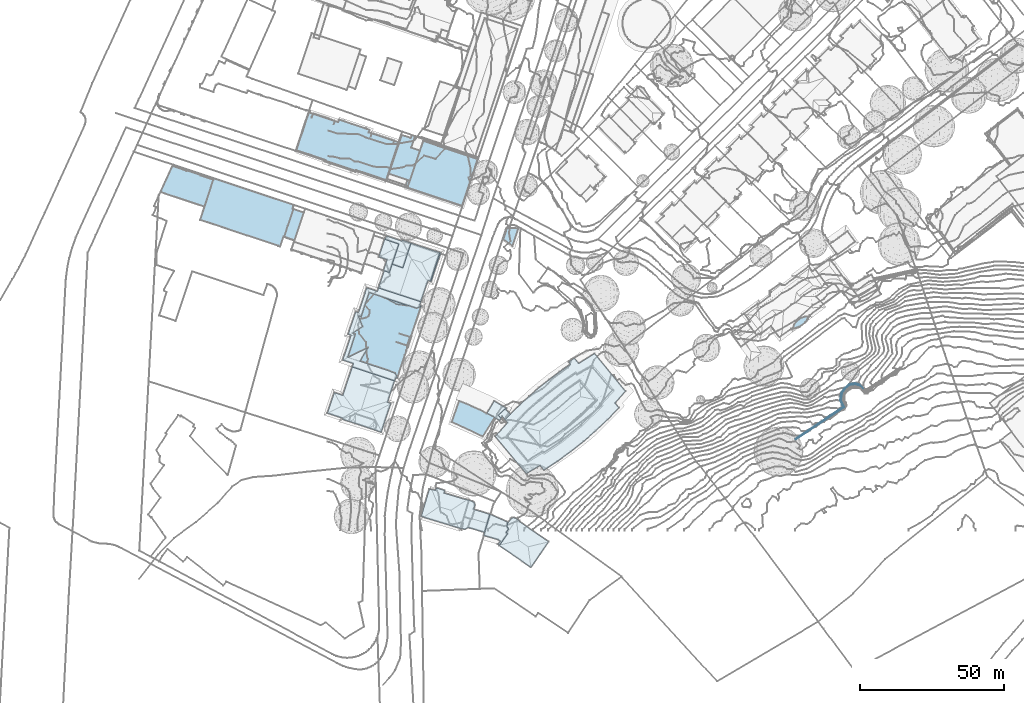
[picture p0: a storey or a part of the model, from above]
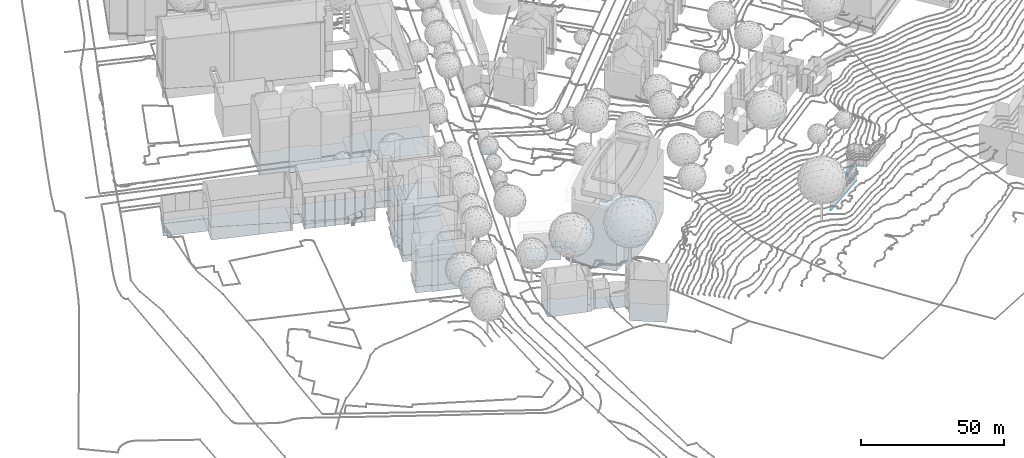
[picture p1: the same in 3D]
Properties of the parts of a building model (IFC4)

# File
Description: ViewDefinition [CoordinationView]
Time: 2024-08-21T15:45:22
Written by: TpxIfclib v0.1
Made in: TpxIfclib v0.1

# IfcGeographicElement (454)
Name | In
TPX_GROUND | TPX_GROUND | PredefinedType: TERRAIN
Cadastre 0 | TPX_CADASTRES
Cadastre 1 | TPX_CADASTRES
Cadastre 2 | TPX_CADASTRES
Cadastre 3 | TPX_CADASTRES
Cadastre 4 | TPX_CADASTRES
Cadastre 5 | TPX_CADASTRES
Cadastre 6 | TPX_CADASTRES
Cadastre 7 | TPX_CADASTRES
Cadastre 8 | TPX_CADASTRES
Cadastre 9 | TPX_CADASTRES
Cadastre 10 | TPX_CADASTRES
Cadastre 11 | TPX_CADASTRES
Cadastre 12 | TPX_CADASTRES
Cadastre 13 | TPX_CADASTRES
Cadastre 14 | TPX_CADASTRES
Cadastre 15 | TPX_CADASTRES
Cadastre 16 | TPX_CADASTRES
Cadastre 17 | TPX_CADASTRES
Cadastre 18 | TPX_CADASTRES
Cadastre 19 | TPX_CADASTRES
Cadastre 20 | TPX_CADASTRES
Cadastre 21 | TPX_CADASTRES
Cadastre 22 | TPX_CADASTRES
Cadastre 23 | TPX_CADASTRES
Cadastre 24 | TPX_CADASTRES
Cadastre 25 | TPX_CADASTRES
Cadastre 26 | TPX_CADASTRES
Cadastre 27 | TPX_CADASTRES
Cadastre 28 | TPX_CADASTRES
Cadastre 29 | TPX_CADASTRES
Cadastre 30 | TPX_CADASTRES
Cadastre 31 | TPX_CADASTRES
Cadastre 32 | TPX_CADASTRES
Cadastre 33 | TPX_CADASTRES
Cadastre 34 | TPX_CADASTRES
Cadastre 35 | TPX_CADASTRES
Cadastre 36 | TPX_CADASTRES
Cadastre 37 | TPX_CADASTRES
Cadastre 38 | TPX_CADASTRES
Cadastre 39 | TPX_CADASTRES
Cadastre 40 | TPX_CADASTRES
Cadastre 41 | TPX_CADASTRES
Cadastre 42 | TPX_CADASTRES
Cadastre 43 | TPX_CADASTRES
Cadastre 44 | TPX_CADASTRES
Cadastre 45 | TPX_CADASTRES
Cadastre 46 | TPX_CADASTRES
Cadastre 47 | TPX_CADASTRES
Cadastre 48 | TPX_CADASTRES
Cadastre 49 | TPX_CADASTRES
Cadastre 50 | TPX_CADASTRES
Cadastre 51 | TPX_CADASTRES
Cadastre 52 | TPX_CADASTRES
Cadastre 53 | TPX_CADASTRES
Cadastre 54 | TPX_CADASTRES
Cadastre 55 | TPX_CADASTRES
Cadastre 56 | TPX_CADASTRES
Cadastre 57 | TPX_CADASTRES
Cadastre 58 | TPX_CADASTRES
Cadastre 59 | TPX_CADASTRES
Cadastre 60 | TPX_CADASTRES
Cadastre 61 | TPX_CADASTRES
Cadastre 62 | TPX_CADASTRES
Cadastre 63 | TPX_CADASTRES
Cadastre 64 | TPX_CADASTRES
Cadastre 65 | TPX_CADASTRES
Cadastre 66 | TPX_CADASTRES
Cadastre 67 | TPX_CADASTRES
Cadastre 68 | TPX_CADASTRES
Cadastre 69 | TPX_CADASTRES
Cadastre 70 | TPX_CADASTRES
Cadastre 71 | TPX_CADASTRES
Cadastre 72 | TPX_CADASTRES
Cadastre 73 | TPX_CADASTRES
Cadastre 74 | TPX_CADASTRES
Cadastre 75 | TPX_CADASTRES
Cadastre 76 | TPX_CADASTRES
Cadastre 77 | TPX_CADASTRES
Cadastre 78 | TPX_CADASTRES
Cadastre 79 | TPX_CADASTRES
Cadastre 80 | TPX_CADASTRES
Cadastre 81 | TPX_CADASTRES
Cadastre 82 | TPX_CADASTRES
Cadastre 83 | TPX_CADASTRES
Cadastre 84 | TPX_CADASTRES
Cadastre 85 | TPX_CADASTRES
Cadastre 86 | TPX_CADASTRES
Cadastre 87 | TPX_CADASTRES
Cadastre 88 | TPX_CADASTRES
Cadastre 89 | TPX_CADASTRES
Cadastre 90 | TPX_CADASTRES
Cadastre 91 | TPX_CADASTRES
Cadastre 92 | TPX_CADASTRES
Cadastre 93 | TPX_CADASTRES
Cadastre 94 | TPX_CADASTRES
Cadastre 95 | TPX_CADASTRES
Cadastre 96 | TPX_CADASTRES
Cadastre 97 | TPX_CADASTRES
Cadastre 98 | TPX_CADASTRES
Cadastre 99 | TPX_CADASTRES
Cadastre 100 | TPX_CADASTRES
Cadastre 101 | TPX_CADASTRES
Cadastre 102 | TPX_CADASTRES
Cadastre 103 | TPX_CADASTRES
Cadastre 104 | TPX_CADASTRES
Cadastre 105 | TPX_CADASTRES
Cadastre 106 | TPX_CADASTRES
Cadastre 107 | TPX_CADASTRES
Cadastre 108 | TPX_CADASTRES
Cadastre 109 | TPX_CADASTRES
Cadastre 110 | TPX_CADASTRES
Cadastre 111 | TPX_CADASTRES
Cadastre 112 | TPX_CADASTRES
Cadastre 113 | TPX_CADASTRES
Cadastre 114 | TPX_CADASTRES
Cadastre 115 | TPX_CADASTRES
Cadastre 116 | TPX_CADASTRES
Cadastre 117 | TPX_CADASTRES
Cadastre 118 | TPX_CADASTRES
Cadastre 119 | TPX_CADASTRES
Cadastre 120 | TPX_CADASTRES
Cadastre 121 | TPX_CADASTRES
Cadastre 122 | TPX_CADASTRES
Cadastre 123 | TPX_CADASTRES
Cadastre 124 | TPX_CADASTRES
Cadastre 125 | TPX_CADASTRES
Cadastre 126 | TPX_CADASTRES
Cadastre 127 | TPX_CADASTRES
Cadastre 128 | TPX_CADASTRES
Cadastre 129 | TPX_CADASTRES
Cadastre 130 | TPX_CADASTRES
Cadastre 131 | TPX_CADASTRES
Cadastre 132 | TPX_CADASTRES
Cadastre 133 | TPX_CADASTRES
Cadastre 134 | TPX_CADASTRES
Cadastre 135 | TPX_CADASTRES
Cadastre 136 | TPX_CADASTRES
Cadastre 137 | TPX_CADASTRES
Cadastre 138 | TPX_CADASTRES
Cadastre 139 | TPX_CADASTRES
Cadastre 140 | TPX_CADASTRES
Cadastre 141 | TPX_CADASTRES
Cadastre 142 | TPX_CADASTRES
Cadastre 143 | TPX_CADASTRES
Cadastre 144 | TPX_CADASTRES
Cadastre 145 | TPX_CADASTRES
Cadastre 146 | TPX_CADASTRES
Cadastre 147 | TPX_CADASTRES
Cadastre 148 | TPX_CADASTRES
Cadastre 149 | TPX_CADASTRES
Cadastre 150 | TPX_CADASTRES
Cadastre 151 | TPX_CADASTRES
Cadastre 152 | TPX_CADASTRES
Cadastre 153 | TPX_CADASTRES
Cadastre 154 | TPX_CADASTRES
Cadastre 155 | TPX_CADASTRES
Cadastre 156 | TPX_CADASTRES
Cadastre 157 | TPX_CADASTRES
Cadastre 158 | TPX_CADASTRES
Cadastre 159 | TPX_CADASTRES
Cadastre 160 | TPX_CADASTRES
Cadastre 161 | TPX_CADASTRES
Cadastre 162 | TPX_CADASTRES
Cadastre 163 | TPX_CADASTRES
Cadastre 164 | TPX_CADASTRES
Cadastre 165 | TPX_CADASTRES
Cadastre 166 | TPX_CADASTRES
Cadastre 167 | TPX_CADASTRES
Cadastre 168 | TPX_CADASTRES
Cadastre 169 | TPX_CADASTRES
Cadastre 170 | TPX_CADASTRES
Cadastre 171 | TPX_CADASTRES
Cadastre 172 | TPX_CADASTRES
Cadastre 173 | TPX_CADASTRES
Cadastre 174 | TPX_CADASTRES
Cadastre 175 | TPX_CADASTRES
Cadastre 176 | TPX_CADASTRES
Cadastre 177 | TPX_CADASTRES
Cadastre 178 | TPX_CADASTRES
Cadastre 179 | TPX_CADASTRES
Cadastre 180 | TPX_CADASTRES
Cadastre 181 | TPX_CADASTRES
Cadastre 182 | TPX_CADASTRES
Cadastre 183 | TPX_CADASTRES
Cadastre 184 | TPX_CADASTRES
Cadastre 185 | TPX_CADASTRES
Cadastre 186 | TPX_CADASTRES
Cadastre 187 | TPX_CADASTRES
Cadastre 188 | TPX_CADASTRES
Cadastre 189 | TPX_CADASTRES
Cadastre 190 | TPX_CADASTRES
Cadastre 191 | TPX_CADASTRES
Cadastre 192 | TPX_CADASTRES
Cadastre 193 | TPX_CADASTRES
Cadastre 194 | TPX_CADASTRES
Cadastre 195 | TPX_CADASTRES
Cadastre 196 | TPX_CADASTRES
Cadastre 197 | TPX_CADASTRES
Cadastre 198 | TPX_CADASTRES
Cadastre 199 | TPX_CADASTRES
Cadastre 200 | TPX_CADASTRES
Cadastre 201 | TPX_CADASTRES
Cadastre 202 | TPX_CADASTRES
Cadastre 203 | TPX_CADASTRES
Cadastre 204 | TPX_CADASTRES
Cadastre 205 | TPX_CADASTRES
Cadastre 206 | TPX_CADASTRES
Cadastre 207 | TPX_CADASTRES
Cadastre 208 | TPX_CADASTRES
Cadastre 209 | TPX_CADASTRES
Cadastre 210 | TPX_CADASTRES
Cadastre 211 | TPX_CADASTRES
Cadastre 212 | TPX_CADASTRES
Cadastre 213 | TPX_CADASTRES
Cadastre 214 | TPX_CADASTRES
Cadastre 215 | TPX_CADASTRES
Cadastre 216 | TPX_CADASTRES
Cadastre 217 | TPX_CADASTRES
Cadastre 218 | TPX_CADASTRES
Cadastre 219 | TPX_CADASTRES
Cadastre 220 | TPX_CADASTRES
Cadastre 221 | TPX_CADASTRES
Cadastre 222 | TPX_CADASTRES
Cadastre 223 | TPX_CADASTRES
Cadastre 224 | TPX_CADASTRES
Cadastre 225 | TPX_CADASTRES
Cadastre 226 | TPX_CADASTRES
Cadastre 227 | TPX_CADASTRES
Cadastre 228 | TPX_CADASTRES
Cadastre 229 | TPX_CADASTRES
Cadastre 230 | TPX_CADASTRES
Cadastre 231 | TPX_CADASTRES
Cadastre 232 | TPX_CADASTRES
Cadastre 233 | TPX_CADASTRES
10 x Contour Line 542.0 m | TPX_CONTOUR_LINES
10 x Contour Line 543.0 m | TPX_CONTOUR_LINES
8 x Contour Line 541.0 m | TPX_CONTOUR_LINES
7 x Contour Line 540.0 m | TPX_CONTOUR_LINES
8 x Contour Line 539.0 m | TPX_CONTOUR_LINES
2 x Contour Line 537.0 m | TPX_CONTOUR_LINES
4 x Contour Line 538.0 m | TPX_CONTOUR_LINES
4 x Contour Line 505.0 m | TPX_CONTOUR_LINES
8 x Contour Line 529.0 m | TPX_CONTOUR_LINES
34 x Contour Line 502.0 m | TPX_CONTOUR_LINES
10 x Contour Line 501.0 m | TPX_CONTOUR_LINES
Contour Line 545.0 m | TPX_CONTOUR_LINES
Contour Line 544.0 m | TPX_CONTOUR_LINES
31 x Contour Line 503.0 m | TPX_CONTOUR_LINES
10 x Contour Line 533.0 m | TPX_CONTOUR_LINES
3 x Contour Line 530.0 m | TPX_CONTOUR_LINES
4 x Contour Line 532.0 m | TPX_CONTOUR_LINES
2 x Contour Line 531.0 m | TPX_CONTOUR_LINES
6 x Contour Line 506.0 m | TPX_CONTOUR_LINES
6 x Contour Line 535.0 m | TPX_CONTOUR_LINES
Contour Line 536.0 m | TPX_CONTOUR_LINES
6 x Contour Line 528.0 m | TPX_CONTOUR_LINES
Contour Line 534.0 m | TPX_CONTOUR_LINES
15 x Contour Line 504.0 m | TPX_CONTOUR_LINES
3 x Contour Line 526.0 m | TPX_CONTOUR_LINES
4 x Contour Line 527.0 m | TPX_CONTOUR_LINES
2 x Contour Line 507.0 m | TPX_CONTOUR_LINES
Contour Line 508.0 m | TPX_CONTOUR_LINES
Contour Line 509.0 m | TPX_CONTOUR_LINES
Contour Line 510.0 m | TPX_CONTOUR_LINES
Contour Line 511.0 m | TPX_CONTOUR_LINES
Contour Line 512.0 m | TPX_CONTOUR_LINES
Contour Line 513.0 m | TPX_CONTOUR_LINES
Contour Line 514.0 m | TPX_CONTOUR_LINES
Contour Line 515.0 m | TPX_CONTOUR_LINES
Contour Line 516.0 m | TPX_CONTOUR_LINES
Contour Line 517.0 m | TPX_CONTOUR_LINES
Contour Line 518.0 m | TPX_CONTOUR_LINES
Contour Line 519.0 m | TPX_CONTOUR_LINES
Contour Line 520.0 m | TPX_CONTOUR_LINES
Contour Line 521.0 m | TPX_CONTOUR_LINES
Contour Line 522.0 m | TPX_CONTOUR_LINES
Contour Line 523.0 m | TPX_CONTOUR_LINES
Contour Line 524.0 m | TPX_CONTOUR_LINES
Contour Line 525.0 m | TPX_CONTOUR_LINES

# IfcGeographicElement: VEGETATION (542)
In: TPX_TREES
PredefinedType: USERDEFINED
Name
3 x Tree TR4 CD138
3 x Tree TR2 CD86
2 x Tree TR1 CD38
3 x Tree TR3 CD95
6 x Tree TR1 CD41
13 x Tree TR1 CD50
4 x Tree TR0 CD27
11 x Tree TR0 CD25
2 x Tree TR0 CD24
Tree TR1 CD36
5 x Tree TR1 CD47
5 x Tree TR1 CD44
11 x Tree TR2 CD76
8 x Tree TR2 CD87
2 x Tree TR0 CD30
Tree TR1 CD43
2 x Tree TR1 CD40
5 x Tree TR1 CD55
4 x Tree TR1 CD58
7 x Tree TR2 CD64
9 x Tree TR2 CD67
12 x Tree TR2 CD70
11 x Tree TR2 CD73
7 x Tree TR2 CD71
9 x Tree TR2 CD68
6 x Tree TR2 CD75
7 x Tree TR1 CD59
7 x Tree TR2 CD78
5 x Tree TR2 CD74
5 x Tree TR2 CD85
9 x Tree TR2 CD69
Tree TR2 CD89
8 x Tree TR2 CD63
8 x Tree TR2 CD83
7 x Tree TR2 CD66
6 x Tree TR3 CD98
8 x Tree TR2 CD65
4 x Tree TR3 CD119
10 x Tree TR1 CD51
4 x Tree TR3 CD124
6 x Tree TR3 CD122
4 x Tree TR3 CD125
9 x Tree TR2 CD92
3 x Tree TR3 CD113
3 x Tree TR3 CD114
3 x Tree TR3 CD112
3 x Tree TR3 CD116
2 x Tree TR5 CD160
5 x Tree TR5 CD185
7 x Tree TR2 CD72
7 x Tree TR1 CD53
3 x Tree TR3 CD103
4 x Tree TR1 CD62
3 x Tree TR1 CD48
6 x Tree TR2 CD82
4 x Tree TR3 CD99
2 x Tree TR5 CD173
3 x Tree TR4 CD141
Tree TR5 CD175
Tree TR6 CD193
8 x Tree TR1 CD52
3 x Tree TR4 CD128
Tree TR6 CD195
5 x Tree TR1 CD49
3 x Tree TR3 CD123
5 x Tree TR1 CD45
Tree TR7 CD226
Tree TR7 CD241
Tree TR7 CD245
Tree TR6 CD219
11 x Tree TR1 CD60
2 x Tree TR3 CD121
4 x Tree TR3 CD102
11 x Tree TR1 CD61
2 x Tree TR4 CD135
7 x Tree TR1 CD54
2 x Tree TR2 CD88
3 x Tree TR1 CD35
3 x Tree TR4 CD130
3 x Tree TR1 CD42
4 x Tree TR3 CD101
3 x Tree TR5 CD187
Tree TR4 CD144
2 x Tree TR5 CD158
2 x Tree TR3 CD118
2 x Tree TR1 CD56
5 x Tree TR1 CD46
Tree TR4 CD145
4 x Tree TR3 CD109
3 x Tree TR4 CD132
Tree TR6 CD194
2 x Tree TR3 CD97
Tree TR3 CD105
6 x Tree TR2 CD80
6 x Tree TR2 CD79
Tree TR4 CD152
4 x Tree TR4 CD153
Tree TR4 CD133
2 x Tree TR5 CD178
3 x Tree TR2 CD93
Tree TR7 CD220
2 x Tree TR6 CD203
3 x Tree TR2 CD90
8 x Tree TR2 CD81
4 x Tree TR4 CD126
4 x Tree TR2 CD84
6 x Tree TR3 CD104
2 x Tree TR4 CD155
3 x Tree TR4 CD142
2 x Tree TR4 CD127
3 x Tree TR3 CD115
Tree TR6 CD198
3 x Tree TR3 CD94
3 x Tree TR4 CD129
Tree TR7 CD221
3 x Tree TR3 CD111
3 x Tree TR2 CD77
2 x Tree TR1 CD39
3 x Tree TR1 CD34
Tree TR3 CD100
Tree TR3 CD106
3 x Tree TR1 CD57
2 x Tree TR1 CD37
4 x Tree TR3 CD96
2 x Tree TR4 CD134
2 x Tree TR5 CD183
Tree TR3 CD117
2 x Tree TR2 CD62
Tree TR4 CD154
Tree TR5 CD174
Tree TR5 CD168
2 x Tree TR3 CD108
Tree TR7 CD222
Tree TR0 CD23
2 x Tree TR1 CD31
Tree TR4 CD147
Tree TR4 CD137
Tree TR4 CD150
Tree TR1 CD32
Tree TR3 CD120
Tree TR5 CD182
Tree TR2 CD91
